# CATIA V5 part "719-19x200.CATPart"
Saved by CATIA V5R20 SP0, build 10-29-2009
Part number: 719-19x200
Definition: NONE
Nomenclature: 719-19x200
Source: Unknown
Description: 719-19x200
Bounding box of the stored display mesh (mm): x 0 to 223, y -12.5 to 12.5, z -12.5 to 12.5
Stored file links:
  C:\Users\Utente\Desktop\IO LAVORO\3D X SITO CF\X SITO\719\719-19x200.CATPart

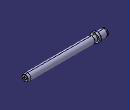
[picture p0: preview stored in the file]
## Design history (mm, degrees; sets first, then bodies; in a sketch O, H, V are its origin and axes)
Body1 "719-19x200" (main body)
  Solid1: solid without history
